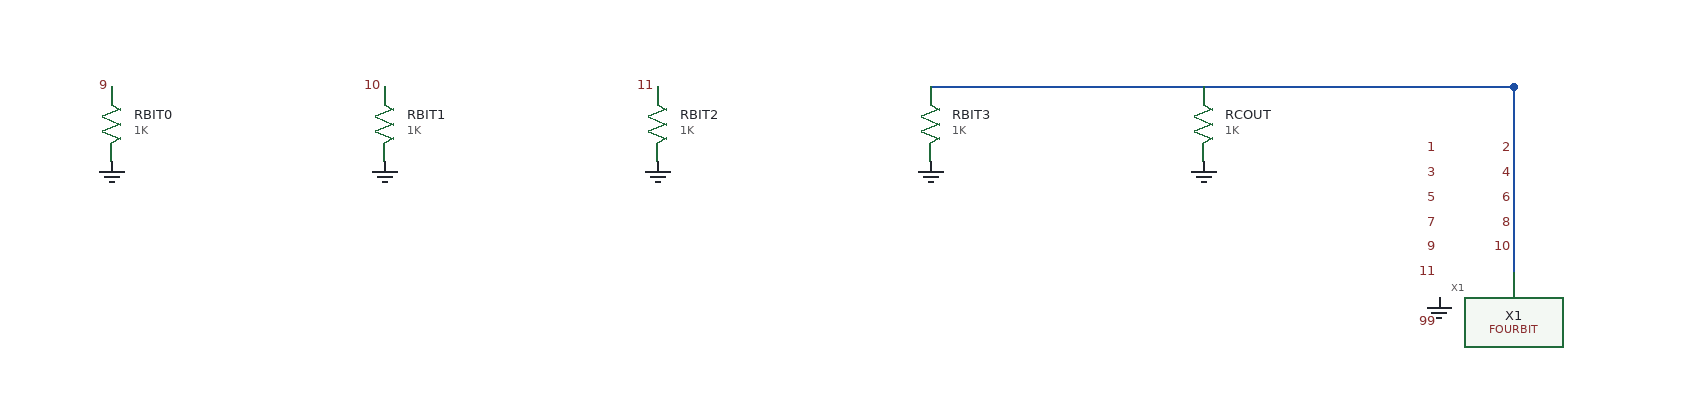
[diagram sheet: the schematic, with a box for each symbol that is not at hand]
v {xschem version=3.4.5 file_version=1.2}
G {}
K {}
V {}
S {}
E {}
C {FOURBIT.sym} 1540 -300 0 0 {name=X1}
C {devices/res.sym} 440 -400 0 0 {name=RBIT0
value=1K}
C {devices/res.sym} 660 -400 0 0 {name=RBIT1
value=1K}
C {devices/res.sym} 880 -400 0 0 {name=RBIT2
value=1K}
C {devices/res.sym} 1100 -400 0 0 {name=RBIT3
value=1K}
C {devices/res.sym} 1320 -400 0 0 {name=RCOUT
value=1K}
T {X1} 1520 -280 0 0 0.25 0.25 {}
N 1570 -280 1570 -430 {lab=12}
N 1570 -430 1100 -430 {lab=12}
N 1570 -260 1570 -430 {lab=13}
N 1570 -430 1320 -430 {lab=13}
C {devices/lab_pin.sym} 1510 -240 0 0 {name=l_99 sig_type=std_logic lab=99}
C {devices/gnd.sym} 1510 -260 0 0 {name=l_0 lab=GND}
C {devices/gnd.sym} 440 -370 0 0 {name=l_0 lab=GND}
C {devices/gnd.sym} 660 -370 0 0 {name=l_0 lab=GND}
C {devices/gnd.sym} 880 -370 0 0 {name=l_0 lab=GND}
C {devices/gnd.sym} 1100 -370 0 0 {name=l_0 lab=GND}
C {devices/gnd.sym} 1320 -370 0 0 {name=l_0 lab=GND}
C {devices/lab_pin.sym} 1510 -380 0 0 {name=l_1 sig_type=std_logic lab=1}
C {devices/lab_pin.sym} 1570 -380 0 0 {name=l_2 sig_type=std_logic lab=2}
C {devices/lab_pin.sym} 1510 -360 0 0 {name=l_3 sig_type=std_logic lab=3}
C {devices/lab_pin.sym} 1570 -360 0 0 {name=l_4 sig_type=std_logic lab=4}
C {devices/lab_pin.sym} 1510 -340 0 0 {name=l_5 sig_type=std_logic lab=5}
C {devices/lab_pin.sym} 1570 -340 0 0 {name=l_6 sig_type=std_logic lab=6}
C {devices/lab_pin.sym} 1510 -320 0 0 {name=l_7 sig_type=std_logic lab=7}
C {devices/lab_pin.sym} 1570 -320 0 0 {name=l_8 sig_type=std_logic lab=8}
C {devices/lab_pin.sym} 1510 -300 0 0 {name=l_9 sig_type=std_logic lab=9}
C {devices/lab_pin.sym} 440 -430 0 0 {name=l_9 sig_type=std_logic lab=9}
C {devices/lab_pin.sym} 1570 -300 0 0 {name=l_10 sig_type=std_logic lab=10}
C {devices/lab_pin.sym} 660 -430 0 0 {name=l_10 sig_type=std_logic lab=10}
C {devices/lab_pin.sym} 1510 -280 0 0 {name=l_11 sig_type=std_logic lab=11}
C {devices/lab_pin.sym} 880 -430 0 0 {name=l_11 sig_type=std_logic lab=11}
